VERSION 5.8 ;
BUSBITCHARS "[]" ;
DIVIDERCHAR "/" ;
UNITS
    DATABASE MICRONS 1000 ;
END UNITS

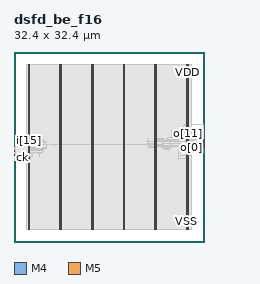
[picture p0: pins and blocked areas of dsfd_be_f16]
MACRO dsfd_be_f16
  FOREIGN dsfd_be_f16 0 0 ;
  CLASS BLOCK ;
  SIZE 32.4 BY 32.4 ;
  PIN ck
    DIRECTION INPUT ;
    USE SIGNAL ;
    PORT
      LAYER M4 ;
        RECT  0 14.448 0.084 14.472 ;
    END
  END ck
  PIN i[0]
    DIRECTION INPUT ;
    USE SIGNAL ;
    PORT
      LAYER M4 ;
        RECT  0 14.544 0.084 14.568 ;
    END
  END i[0]
  PIN i[10]
    DIRECTION INPUT ;
    USE SIGNAL ;
    PORT
      LAYER M4 ;
        RECT  0 15.504 0.084 15.528 ;
    END
  END i[10]
  PIN i[11]
    DIRECTION INPUT ;
    USE SIGNAL ;
    PORT
      LAYER M4 ;
        RECT  0 15.6 0.084 15.624 ;
    END
  END i[11]
  PIN i[12]
    DIRECTION INPUT ;
    USE SIGNAL ;
    PORT
      LAYER M4 ;
        RECT  0 15.696 0.084 15.72 ;
    END
  END i[12]
  PIN i[13]
    DIRECTION INPUT ;
    USE SIGNAL ;
    PORT
      LAYER M4 ;
        RECT  0 15.792 0.084 15.816 ;
    END
  END i[13]
  PIN i[14]
    DIRECTION INPUT ;
    USE SIGNAL ;
    PORT
      LAYER M4 ;
        RECT  0 15.888 0.084 15.912 ;
    END
  END i[14]
  PIN i[15]
    DIRECTION INPUT ;
    USE SIGNAL ;
    PORT
      LAYER M4 ;
        RECT  0 15.984 0.084 16.008 ;
    END
  END i[15]
  PIN i[1]
    DIRECTION INPUT ;
    USE SIGNAL ;
    PORT
      LAYER M4 ;
        RECT  0 14.64 0.084 14.664 ;
    END
  END i[1]
  PIN i[2]
    DIRECTION INPUT ;
    USE SIGNAL ;
    PORT
      LAYER M4 ;
        RECT  0 14.736 0.084 14.76 ;
    END
  END i[2]
  PIN i[3]
    DIRECTION INPUT ;
    USE SIGNAL ;
    PORT
      LAYER M4 ;
        RECT  0 14.832 0.084 14.856 ;
    END
  END i[3]
  PIN i[4]
    DIRECTION INPUT ;
    USE SIGNAL ;
    PORT
      LAYER M4 ;
        RECT  0 14.928 0.084 14.952 ;
    END
  END i[4]
  PIN i[5]
    DIRECTION INPUT ;
    USE SIGNAL ;
    PORT
      LAYER M4 ;
        RECT  0 15.024 0.084 15.048 ;
    END
  END i[5]
  PIN i[6]
    DIRECTION INPUT ;
    USE SIGNAL ;
    PORT
      LAYER M4 ;
        RECT  0 15.12 0.084 15.144 ;
    END
  END i[6]
  PIN i[7]
    DIRECTION INPUT ;
    USE SIGNAL ;
    PORT
      LAYER M4 ;
        RECT  0 15.216 0.084 15.24 ;
    END
  END i[7]
  PIN i[8]
    DIRECTION INPUT ;
    USE SIGNAL ;
    PORT
      LAYER M4 ;
        RECT  0 15.312 0.084 15.336 ;
    END
  END i[8]
  PIN i[9]
    DIRECTION INPUT ;
    USE SIGNAL ;
    PORT
      LAYER M4 ;
        RECT  0 15.408 0.084 15.432 ;
    END
  END i[9]
  PIN o[0]
    DIRECTION OUTPUT ;
    USE SIGNAL ;
    PORT
      LAYER M4 ;
        RECT  32.316 16.08 32.4 16.104 ;
    END
  END o[0]
  PIN o[10]
    DIRECTION OUTPUT ;
    USE SIGNAL ;
    PORT
      LAYER M4 ;
        RECT  32.316 17.04 32.4 17.064 ;
    END
  END o[10]
  PIN o[11]
    DIRECTION OUTPUT ;
    USE SIGNAL ;
    PORT
      LAYER M4 ;
        RECT  32.316 17.136 32.4 17.16 ;
    END
  END o[11]
  PIN o[12]
    DIRECTION OUTPUT ;
    USE SIGNAL ;
    PORT
      LAYER M4 ;
        RECT  32.316 17.232 32.4 17.256 ;
    END
  END o[12]
  PIN o[13]
    DIRECTION OUTPUT ;
    USE SIGNAL ;
    PORT
      LAYER M4 ;
        RECT  32.316 17.328 32.4 17.352 ;
    END
  END o[13]
  PIN o[14]
    DIRECTION OUTPUT ;
    USE SIGNAL ;
    PORT
      LAYER M4 ;
        RECT  32.316 17.424 32.4 17.448 ;
    END
  END o[14]
  PIN o[15]
    DIRECTION OUTPUT ;
    USE SIGNAL ;
    PORT
      LAYER M4 ;
        RECT  32.316 17.52 32.4 17.544 ;
    END
  END o[15]
  PIN o[1]
    DIRECTION OUTPUT ;
    USE SIGNAL ;
    PORT
      LAYER M4 ;
        RECT  32.316 16.176 32.4 16.2 ;
    END
  END o[1]
  PIN o[2]
    DIRECTION OUTPUT ;
    USE SIGNAL ;
    PORT
      LAYER M4 ;
        RECT  32.316 16.272 32.4 16.296 ;
    END
  END o[2]
  PIN o[3]
    DIRECTION OUTPUT ;
    USE SIGNAL ;
    PORT
      LAYER M4 ;
        RECT  32.316 16.368 32.4 16.392 ;
    END
  END o[3]
  PIN o[4]
    DIRECTION OUTPUT ;
    USE SIGNAL ;
    PORT
      LAYER M4 ;
        RECT  32.316 16.464 32.4 16.488 ;
    END
  END o[4]
  PIN o[5]
    DIRECTION OUTPUT ;
    USE SIGNAL ;
    PORT
      LAYER M4 ;
        RECT  32.316 16.56 32.4 16.584 ;
    END
  END o[5]
  PIN o[6]
    DIRECTION OUTPUT ;
    USE SIGNAL ;
    PORT
      LAYER M4 ;
        RECT  32.316 16.656 32.4 16.68 ;
    END
  END o[6]
  PIN o[7]
    DIRECTION OUTPUT ;
    USE SIGNAL ;
    PORT
      LAYER M4 ;
        RECT  32.316 16.752 32.4 16.776 ;
    END
  END o[7]
  PIN o[8]
    DIRECTION OUTPUT ;
    USE SIGNAL ;
    PORT
      LAYER M4 ;
        RECT  32.316 16.848 32.4 16.872 ;
    END
  END o[8]
  PIN o[9]
    DIRECTION OUTPUT ;
    USE SIGNAL ;
    PORT
      LAYER M4 ;
        RECT  32.316 16.944 32.4 16.968 ;
    END
  END o[9]
  PIN rn
    DIRECTION INPUT ;
    USE SIGNAL ;
    PORT
      LAYER M4 ;
        RECT  0 16.08 0.084 16.104 ;
    END
  END rn
  PIN VDD
    DIRECTION INOUT ;
    USE POWER ;
    PORT
      LAYER M5 ;
        RECT  29.592 2.151 29.712 30.249 ;
        RECT  24.192 2.151 24.312 30.249 ;
        RECT  18.792 2.151 18.912 30.249 ;
        RECT  13.392 2.151 13.512 30.249 ;
        RECT  7.992 2.151 8.112 30.249 ;
        RECT  2.592 2.151 2.712 30.249 ;
    END
  END VDD
  PIN VSS
    DIRECTION INOUT ;
    USE GROUND ;
    PORT
      LAYER M5 ;
        RECT  29.4 2.137 29.52 30.263 ;
        RECT  24 2.137 24.12 30.263 ;
        RECT  18.6 2.137 18.72 30.263 ;
        RECT  13.2 2.137 13.32 30.263 ;
        RECT  7.8 2.137 7.92 30.263 ;
        RECT  2.4 2.137 2.52 30.263 ;
    END
  END VSS
  # OT_OBS_CLOSED layer=M5 d_um=1.536 added=0
  OBS
    LAYER RVTN ;
     RECT  2.16 2.16 30.24 2.295 ;
     RECT  2.16 2.565 30.24 2.835 ;
     RECT  2.16 3.105 30.24 3.375 ;
     RECT  2.16 3.645 30.24 3.915 ;
     RECT  2.16 4.185 30.24 4.455 ;
     RECT  2.16 4.725 30.24 4.995 ;
     RECT  2.16 5.265 30.24 5.535 ;
     RECT  2.16 5.805 30.24 6.075 ;
     RECT  2.16 6.345 30.24 6.615 ;
     RECT  2.16 6.885 30.24 7.155 ;
     RECT  2.16 7.425 30.24 7.695 ;
     RECT  2.16 7.965 30.24 8.235 ;
     RECT  2.16 8.505 30.24 8.775 ;
     RECT  2.16 9.045 30.24 9.315 ;
     RECT  2.16 9.585 30.24 9.855 ;
     RECT  2.16 10.125 30.24 10.395 ;
     RECT  2.16 10.665 30.24 10.935 ;
     RECT  2.16 11.205 30.24 11.475 ;
     RECT  2.16 11.745 30.24 12.015 ;
     RECT  2.16 12.285 30.24 12.555 ;
     RECT  2.16 12.825 30.24 13.095 ;
     RECT  2.16 13.365 30.24 13.635 ;
     RECT  2.16 13.905 30.24 14.175 ;
     RECT  2.16 14.445 30.24 14.715 ;
     RECT  2.16 14.985 30.24 15.255 ;
     RECT  2.16 15.525 30.24 15.795 ;
     RECT  2.16 16.065 30.24 16.335 ;
     RECT  2.16 16.605 30.24 16.875 ;
     RECT  2.16 17.145 30.24 17.415 ;
     RECT  2.16 17.685 30.24 17.955 ;
     RECT  2.16 18.225 30.24 18.495 ;
     RECT  2.16 18.765 30.24 19.035 ;
     RECT  2.16 19.305 30.24 19.575 ;
     RECT  2.16 19.845 30.24 20.115 ;
     RECT  2.16 20.385 30.24 20.655 ;
     RECT  2.16 20.925 30.24 21.195 ;
     RECT  2.16 21.465 30.24 21.735 ;
     RECT  2.16 22.005 30.24 22.275 ;
     RECT  2.16 22.545 30.24 22.815 ;
     RECT  2.16 23.085 30.24 23.355 ;
     RECT  2.16 23.625 30.24 23.895 ;
     RECT  2.16 24.165 30.24 24.435 ;
     RECT  2.16 24.705 30.24 24.975 ;
     RECT  2.16 25.245 30.24 25.515 ;
     RECT  2.16 25.785 30.24 26.055 ;
     RECT  2.16 26.325 30.24 26.595 ;
     RECT  2.16 26.865 30.24 27.135 ;
     RECT  2.16 27.405 30.24 27.675 ;
     RECT  2.16 27.945 30.24 28.215 ;
     RECT  2.16 28.485 30.24 28.755 ;
     RECT  2.16 29.025 30.24 29.295 ;
     RECT  2.16 29.565 30.24 29.835 ;
     RECT  2.16 30.105 30.24 30.24 ;
    LAYER RVTP ;
     RECT  2.16 2.295 30.24 2.565 ;
     RECT  2.16 2.835 30.24 3.105 ;
     RECT  2.16 3.375 30.24 3.645 ;
     RECT  2.16 3.915 30.24 4.185 ;
     RECT  2.16 4.455 30.24 4.725 ;
     RECT  2.16 4.995 30.24 5.265 ;
     RECT  2.16 5.535 30.24 5.805 ;
     RECT  2.16 6.075 30.24 6.345 ;
     RECT  2.16 6.615 30.24 6.885 ;
     RECT  2.16 7.155 30.24 7.425 ;
     RECT  2.16 7.695 30.24 7.965 ;
     RECT  2.16 8.235 30.24 8.505 ;
     RECT  2.16 8.775 30.24 9.045 ;
     RECT  2.16 9.315 30.24 9.585 ;
     RECT  2.16 9.855 30.24 10.125 ;
     RECT  2.16 10.395 30.24 10.665 ;
     RECT  2.16 10.935 30.24 11.205 ;
     RECT  2.16 11.475 30.24 11.745 ;
     RECT  2.16 12.015 30.24 12.285 ;
     RECT  2.16 12.555 30.24 12.825 ;
     RECT  2.16 13.095 30.24 13.365 ;
     RECT  2.16 13.635 30.24 13.905 ;
     RECT  2.16 14.175 30.24 14.445 ;
     RECT  2.16 14.715 30.24 14.985 ;
     RECT  2.16 15.255 30.24 15.525 ;
     RECT  2.16 15.795 30.24 16.065 ;
     RECT  2.16 16.335 30.24 16.605 ;
     RECT  2.16 16.875 30.24 17.145 ;
     RECT  2.16 17.415 30.24 17.685 ;
     RECT  2.16 17.955 30.24 18.225 ;
     RECT  2.16 18.495 30.24 18.765 ;
     RECT  2.16 19.035 30.24 19.305 ;
     RECT  2.16 19.575 30.24 19.845 ;
     RECT  2.16 20.115 30.24 20.385 ;
     RECT  2.16 20.655 30.24 20.925 ;
     RECT  2.16 21.195 30.24 21.465 ;
     RECT  2.16 21.735 30.24 22.005 ;
     RECT  2.16 22.275 30.24 22.545 ;
     RECT  2.16 22.815 30.24 23.085 ;
     RECT  2.16 23.355 30.24 23.625 ;
     RECT  2.16 23.895 30.24 24.165 ;
     RECT  2.16 24.435 30.24 24.705 ;
     RECT  2.16 24.975 30.24 25.245 ;
     RECT  2.16 25.515 30.24 25.785 ;
     RECT  2.16 26.055 30.24 26.325 ;
     RECT  2.16 26.595 30.24 26.865 ;
     RECT  2.16 27.135 30.24 27.405 ;
     RECT  2.16 27.675 30.24 27.945 ;
     RECT  2.16 28.215 30.24 28.485 ;
     RECT  2.16 28.755 30.24 29.025 ;
     RECT  2.16 29.295 30.24 29.565 ;
     RECT  2.16 29.835 30.24 30.105 ;
    LAYER M1 ;
     RECT  2.16 2.151 30.24 30.249 ;
    LAYER M2 ;
     RECT  0.103 13.95 0.139 13.968 ;
     RECT  0.103 14.76 0.139 14.778 ;
     RECT  0.139 13.95 2.16 14.778 ;
     RECT  2.16 2.151 30.24 30.249 ;
     RECT  30.24 18.936 30.731 19.224 ;
     RECT  30.731 18.936 30.767 18.954 ;
     RECT  30.24 15.228 30.803 15.246 ;
     RECT  30.24 16.146 31.307 17.604 ;
     RECT  31.307 16.146 31.343 17.334 ;
     RECT  31.343 16.146 31.379 16.974 ;
     RECT  31.379 16.506 31.415 16.524 ;
     RECT  30.24 20.016 32.387 20.034 ;
    LAYER M3 ;
     RECT  2.415 2.143 2.505 2.413 ;
     RECT  7.815 2.143 7.905 2.413 ;
     RECT  13.215 2.143 13.305 2.413 ;
     RECT  18.615 2.143 18.705 2.413 ;
     RECT  24.015 2.143 24.105 2.413 ;
     RECT  29.415 2.143 29.505 2.413 ;
     RECT  2.415 2.413 2.697 14.071 ;
     RECT  0.108 13.945 0.126 14.215 ;
     RECT  27.972 14.071 27.99 14.251 ;
     RECT  29.415 2.413 29.697 14.251 ;
     RECT  0.108 14.215 0.162 14.485 ;
     RECT  2.415 14.071 2.754 14.521 ;
     RECT  2.415 14.521 3.114 14.731 ;
     RECT  27.972 14.251 29.697 14.755 ;
     RECT  27.972 14.755 29.934 14.791 ;
     RECT  0.108 14.485 0.198 14.957 ;
     RECT  2.304 14.731 3.114 15.061 ;
     RECT  4.356 14.611 4.374 15.061 ;
     RECT  0.108 14.957 0.126 15.149 ;
     RECT  4.356 15.061 4.59 15.151 ;
     RECT  27.972 14.791 30.15 15.223 ;
     RECT  2.304 15.061 3.222 15.331 ;
     RECT  3.996 15.151 4.59 15.331 ;
     RECT  2.304 15.331 4.842 15.529 ;
     RECT  2.232 15.529 4.842 15.565 ;
     RECT  2.232 15.565 5.058 15.725 ;
     RECT  26.28 15.601 26.298 15.727 ;
     RECT  25.632 15.727 26.298 15.961 ;
     RECT  25.38 15.961 26.298 15.979 ;
     RECT  2.268 15.725 5.058 16.027 ;
     RECT  25.38 15.979 26.73 16.033 ;
     RECT  25.308 16.033 26.73 16.069 ;
     RECT  2.268 16.027 5.562 16.097 ;
     RECT  22.896 16.033 22.914 16.105 ;
     RECT  24.015 2.413 24.297 16.105 ;
     RECT  25.308 16.069 26.802 16.141 ;
     RECT  27.972 15.223 30.798 16.141 ;
     RECT  2.268 16.097 5.49 16.169 ;
     RECT  25.236 16.141 26.91 16.231 ;
     RECT  27.972 16.141 31.374 16.231 ;
     RECT  22.896 16.105 24.297 16.267 ;
     RECT  25.236 16.231 31.374 16.267 ;
     RECT  6.84 16.231 6.858 16.403 ;
     RECT  22.896 16.267 31.374 16.501 ;
     RECT  22.896 16.501 31.41 16.781 ;
     RECT  22.896 16.781 31.374 16.879 ;
     RECT  2.268 16.169 5.418 16.951 ;
     RECT  2.268 16.951 5.49 16.979 ;
     RECT  2.304 16.979 5.49 17.069 ;
     RECT  22.824 16.879 31.374 17.069 ;
     RECT  2.304 17.069 5.202 17.105 ;
     RECT  23.94 17.069 31.374 17.165 ;
     RECT  23.94 17.165 31.338 17.339 ;
     RECT  2.304 17.105 4.95 17.375 ;
     RECT  23.94 17.339 31.302 17.375 ;
     RECT  4.86 17.375 4.95 17.411 ;
     RECT  22.824 17.069 22.914 17.411 ;
     RECT  24.015 17.375 31.302 17.411 ;
     RECT  4.932 17.411 4.95 17.447 ;
     RECT  2.304 17.375 3.87 17.519 ;
     RECT  26.244 17.411 31.302 17.519 ;
     RECT  2.304 17.519 3.294 17.609 ;
     RECT  22.824 17.411 22.842 17.609 ;
     RECT  24.015 17.411 25.47 17.609 ;
     RECT  30.708 17.519 31.302 17.609 ;
     RECT  32.292 17.515 32.31 17.611 ;
     RECT  2.304 17.609 2.697 17.645 ;
     RECT  32.292 17.611 32.382 17.645 ;
     RECT  24.015 17.609 24.858 17.681 ;
     RECT  26.244 17.519 29.934 17.879 ;
     RECT  26.784 17.879 29.898 18.689 ;
     RECT  26.784 18.689 27.378 18.761 ;
     RECT  28.368 18.689 29.898 18.841 ;
     RECT  26.784 18.761 26.802 18.959 ;
     RECT  30.708 17.609 30.762 18.959 ;
     RECT  30.708 18.959 30.726 19.229 ;
     RECT  28.368 18.841 29.934 19.301 ;
     RECT  28.368 19.301 29.697 19.499 ;
     RECT  28.836 19.499 29.697 19.805 ;
     RECT  32.364 17.645 32.382 20.039 ;
     RECT  29.124 19.805 29.697 20.075 ;
     RECT  2.415 17.645 2.697 29.987 ;
     RECT  7.815 2.413 8.097 29.987 ;
     RECT  13.215 2.413 13.497 29.987 ;
     RECT  18.615 2.413 18.897 29.987 ;
     RECT  24.015 17.681 24.297 29.987 ;
     RECT  29.415 20.075 29.697 29.987 ;
     RECT  2.415 29.987 2.505 30.257 ;
     RECT  7.815 29.987 7.905 30.257 ;
     RECT  13.215 29.987 13.305 30.257 ;
     RECT  18.615 29.987 18.705 30.257 ;
     RECT  24.015 29.987 24.105 30.257 ;
     RECT  29.415 29.987 29.505 30.257 ;
    LAYER M4 ;
     RECT  0.06 14.448 0.181 16.104 ;
     RECT  0.181 14.448 0.227 16.632 ;
     RECT  0.227 14.736 2.408 16.632 ;
     RECT  2.408 2.148 2.512 30.252 ;
     RECT  2.512 2.418 2.704 29.982 ;
     RECT  2.704 15.984 2.765 16.632 ;
     RECT  2.765 16.608 4.633 16.632 ;
     RECT  4.633 16.032 5.573 16.632 ;
     RECT  5.573 16.608 7.808 16.632 ;
     RECT  7.808 2.148 7.912 30.252 ;
     RECT  7.912 2.418 8.104 29.982 ;
     RECT  8.104 16.608 13.208 16.632 ;
     RECT  13.208 2.148 13.312 30.252 ;
     RECT  13.312 2.418 13.504 29.982 ;
     RECT  13.504 16.608 18.608 16.632 ;
     RECT  18.608 2.148 18.712 30.252 ;
     RECT  18.712 2.418 18.904 29.982 ;
     RECT  18.904 16.608 23.245 16.632 ;
     RECT  23.245 16.368 24.008 16.632 ;
     RECT  24.008 2.148 24.112 30.252 ;
     RECT  24.112 2.418 24.304 29.982 ;
     RECT  24.304 16.608 25.369 17.112 ;
     RECT  25.369 16.08 25.481 17.112 ;
     RECT  25.481 16.08 26.125 16.104 ;
     RECT  26.125 15.984 26.701 16.104 ;
     RECT  25.481 17.088 26.701 17.112 ;
     RECT  26.701 15.984 26.741 17.112 ;
     RECT  26.741 16.08 26.813 16.536 ;
     RECT  26.813 16.512 27.641 16.536 ;
     RECT  29.408 2.148 29.512 30.252 ;
     RECT  29.512 2.418 29.704 29.982 ;
     RECT  29.704 16.08 30.697 16.584 ;
     RECT  30.697 16.08 32.281 17.448 ;
     RECT  32.281 16.08 32.364 17.64 ;
     RECT  32.364 17.616 32.393 17.64 ;
    LAYER M5 ;
     RECT  2.4 2.137 2.52 2.151 ;
     RECT  7.8 2.137 7.92 2.151 ;
     RECT  13.2 2.137 13.32 2.151 ;
     RECT  18.6 2.137 18.72 2.151 ;
     RECT  24 2.137 24.12 2.151 ;
     RECT  29.4 2.137 29.52 2.151 ;
     RECT  0.192 14.437 0.216 16.643 ;
     RECT  2.4 2.151 2.712 30.249 ;
     RECT  7.8 2.151 8.112 30.249 ;
     RECT  13.2 2.151 13.512 30.249 ;
     RECT  18.6 2.151 18.912 30.249 ;
     RECT  24 2.151 24.312 30.249 ;
     RECT  29.4 2.151 29.712 30.249 ;
     RECT  2.4 30.249 2.52 30.263 ;
     RECT  7.8 30.249 7.92 30.263 ;
     RECT  13.2 30.249 13.32 30.263 ;
     RECT  18.6 30.249 18.72 30.263 ;
     RECT  24 30.249 24.12 30.263 ;
     RECT  29.4 30.249 29.52 30.263 ;
  END
END dsfd_be_f16
END LIBRARY
